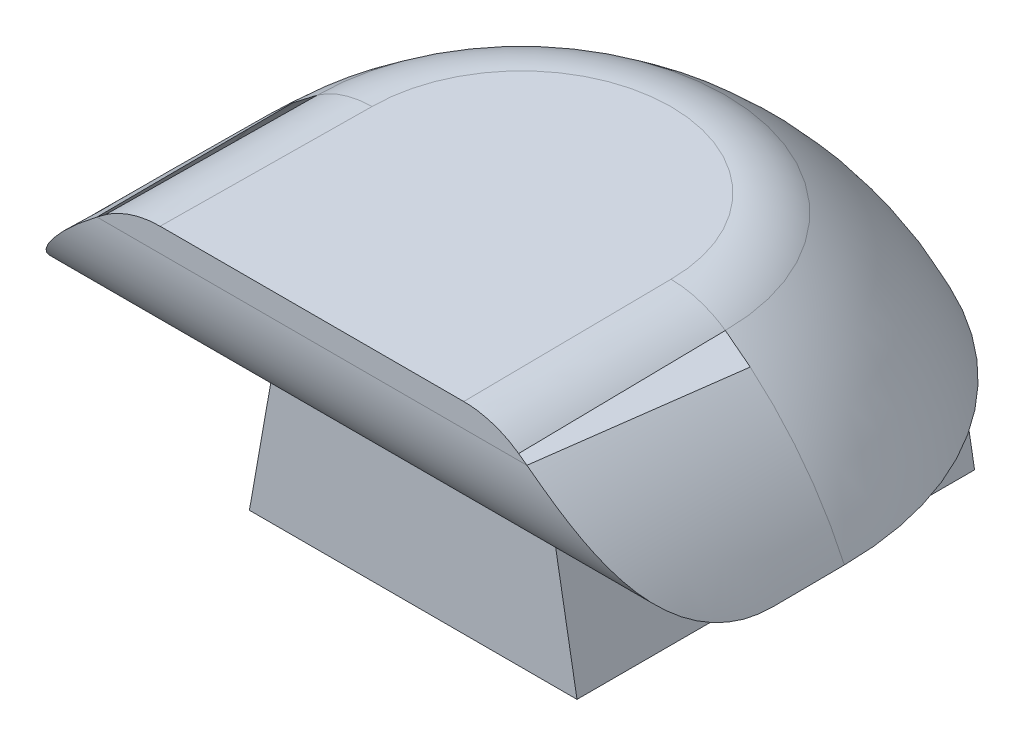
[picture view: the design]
ISO-10303-21;
HEADER;
FILE_DESCRIPTION(('STEP AP214'),'2;1');
FILE_NAME('part.step','',(''),(''),'','','');
FILE_SCHEMA(('AUTOMOTIVE_DESIGN { 1 0 10303 214 1 1 1 1 }'));
ENDSEC;
DATA;
#1=APPLICATION_CONTEXT('core data for automotive mechanical design processes');
#2=APPLICATION_PROTOCOL_DEFINITION('international standard','automotive_design',2000,#1);
#3=PRODUCT_CONTEXT('',#1,'mechanical');
#4=PRODUCT('Part','Part','',(#3));
#5=PRODUCT_RELATED_PRODUCT_CATEGORY('part','',(#4));
#6=PRODUCT_DEFINITION_FORMATION('','',#4);
#7=PRODUCT_DEFINITION_CONTEXT('part definition',#1,'design');
#8=PRODUCT_DEFINITION('design','',#6,#7);
#9=PRODUCT_DEFINITION_SHAPE('','',#8);
#10=(LENGTH_UNIT() NAMED_UNIT(*) SI_UNIT(.MILLI.,.METRE.));
#11=(NAMED_UNIT(*) PLANE_ANGLE_UNIT() SI_UNIT($,.RADIAN.));
#12=(NAMED_UNIT(*) SI_UNIT($,.STERADIAN.) SOLID_ANGLE_UNIT());
#13=UNCERTAINTY_MEASURE_WITH_UNIT(LENGTH_MEASURE(1.E-05),#10,'distance_accuracy_value','');
#14=(GEOMETRIC_REPRESENTATION_CONTEXT(3) GLOBAL_UNCERTAINTY_ASSIGNED_CONTEXT((#13)) GLOBAL_UNIT_ASSIGNED_CONTEXT((#10,
#11,#12)) REPRESENTATION_CONTEXT('',''));
#15=CARTESIAN_POINT('',(0.,0.,0.));
#16=DIRECTION('',(0.,0.,1.));
#17=DIRECTION('',(1.,0.,0.));
#18=AXIS2_PLACEMENT_3D('',#15,#16,#17);
#19=CARTESIAN_POINT('',(-82.1732035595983,3.1,-114.872611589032));
#20=DIRECTION('',(0.,1.,0.));
#21=DIRECTION('',(0.,0.,1.));
#22=AXIS2_PLACEMENT_3D('',#19,#20,#21);
#23=PLANE('',#22);
#24=DIRECTION('',(0.,0.,1.));
#25=VECTOR('',#24,1.);
#26=CARTESIAN_POINT('',(2.93503923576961,3.1,-114.872611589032));
#27=LINE('',#26,#25);
#28=CARTESIAN_POINT('',(2.93503923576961,3.09999999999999,-62.4463343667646));
#29=VERTEX_POINT('',#28);
#30=CARTESIAN_POINT('',(2.93503923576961,3.09999999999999,-54.7963261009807));
#31=VERTEX_POINT('',#30);
#32=EDGE_CURVE('E11',#29,#31,#27,.T.);
#33=ORIENTED_EDGE('',*,*,#32,.F.);
#34=DIRECTION('',(-1.,0.,0.));
#35=VECTOR('',#34,1.);
#36=CARTESIAN_POINT('',(2.93503923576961,3.09999999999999,-62.4463343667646));
#37=LINE('',#36,#35);
#38=CARTESIAN_POINT('',(-2.93503923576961,3.09999999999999,-62.4463343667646));
#39=VERTEX_POINT('',#38);
#40=EDGE_CURVE('E54',#29,#39,#37,.T.);
#41=ORIENTED_EDGE('',*,*,#40,.T.);
#42=DIRECTION('',(0.,0.,-1.));
#43=VECTOR('',#42,1.);
#44=CARTESIAN_POINT('',(-2.93503923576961,3.1,-114.872611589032));
#45=LINE('',#44,#43);
#46=CARTESIAN_POINT('',(-2.93503923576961,3.09999999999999,-54.7963261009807));
#47=VERTEX_POINT('',#46);
#48=EDGE_CURVE('E47',#47,#39,#45,.T.);
#49=ORIENTED_EDGE('',*,*,#48,.F.);
#50=DIRECTION('',(1.,0.,0.));
#51=VECTOR('',#50,1.);
#52=CARTESIAN_POINT('',(-82.1732035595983,3.09999999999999,-54.7963261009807));
#53=LINE('',#52,#51);
#54=CARTESIAN_POINT('',(-6.84025696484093,3.09999999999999,-54.7963261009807));
#55=VERTEX_POINT('',#54);
#56=EDGE_CURVE('E166',#55,#47,#53,.T.);
#57=ORIENTED_EDGE('',*,*,#56,.F.);
#58=CARTESIAN_POINT('',(-6.84025696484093,3.09999999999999,-54.7963261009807));
#59=CARTESIAN_POINT('',(-6.83662078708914,3.09999999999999,-55.3065908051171));
#60=CARTESIAN_POINT('',(-6.83298460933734,3.09999999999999,-55.8168555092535));
#61=CARTESIAN_POINT('',(-6.82934843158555,3.09999999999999,-56.3271202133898));
#62=B_SPLINE_CURVE_WITH_KNOTS('',3,(#58,#59,#60,#61),.UNSPECIFIED.,.F.,.F.,(4,4),(0.,
1.53083297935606),.UNSPECIFIED.);
#63=CARTESIAN_POINT('',(-6.82934843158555,3.09999999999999,-56.3271202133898));
#64=VERTEX_POINT('',#63);
#65=EDGE_CURVE('E435',#55,#64,#62,.T.);
#66=ORIENTED_EDGE('',*,*,#65,.T.);
#67=CARTESIAN_POINT('',(0.,3.09999999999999,-56.3271202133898));
#68=DIRECTION('',(0.,1.,0.));
#69=DIRECTION('',(0.,0.,1.));
#70=AXIS2_PLACEMENT_3D('',#67,#68,#69);
#71=CIRCLE('',#70,6.82934827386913);
#72=CARTESIAN_POINT('',(6.82934827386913,3.09999999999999,-56.3271202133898));
#73=VERTEX_POINT('',#72);
#74=EDGE_CURVE('E289',#73,#64,#71,.T.);
#75=ORIENTED_EDGE('',*,*,#74,.F.);
#76=CARTESIAN_POINT('',(6.82934843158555,3.09999999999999,-56.3271202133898));
#77=CARTESIAN_POINT('',(6.83298460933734,3.09999999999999,-55.8168555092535));
#78=CARTESIAN_POINT('',(6.83662078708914,3.09999999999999,-55.3065908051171));
#79=CARTESIAN_POINT('',(6.84025696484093,3.09999999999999,-54.7963261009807));
#80=B_SPLINE_CURVE_WITH_KNOTS('',3,(#76,#77,#78,#79),.UNSPECIFIED.,.F.,.F.,(4,4),(0.,
1.53083297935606),.UNSPECIFIED.);
#81=CARTESIAN_POINT('',(6.84025696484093,3.09999999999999,-54.7963261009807));
#82=VERTEX_POINT('',#81);
#83=EDGE_CURVE('E234',#73,#82,#80,.T.);
#84=ORIENTED_EDGE('',*,*,#83,.T.);
#85=EDGE_CURVE('E60',#31,#82,#53,.T.);
#86=ORIENTED_EDGE('',*,*,#85,.F.);
#87=EDGE_LOOP('',(#33,#41,#49,#57,#66,#75,#84,#86));
#88=FACE_BOUND('',#87,.T.);
#89=ADVANCED_FACE('F39',(#88),#23,.F.);
#90=CARTESIAN_POINT('',(-4.,-1.95755957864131,-49.8271202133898));
#91=DIRECTION('',(-1.,0.,0.));
#92=DIRECTION('',(0.,0.,1.));
#93=AXIS2_PLACEMENT_3D('',#90,#91,#92);
#94=CYLINDRICAL_SURFACE('',#93,6.5);
#95=CARTESIAN_POINT('',(-3.45109586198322,-1.95755957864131,-49.8271202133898));
#96=DIRECTION('',(-0.999969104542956,0.,-0.00786065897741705));
#97=DIRECTION('',(-0.00786065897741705,0.,0.999969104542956));
#98=AXIS2_PLACEMENT_3D('',#95,#96,#97);
#99=ELLIPSE('',#98,6.50020082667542,6.5);
#100=CARTESIAN_POINT('',(-3.42224907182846,3.40747903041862,-53.4967742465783));
#101=VERTEX_POINT('',#100);
#102=CARTESIAN_POINT('',(-3.42586161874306,3.69445677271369,-53.0372154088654));
#103=VERTEX_POINT('',#102);
#104=EDGE_CURVE('E484',#101,#103,#99,.F.);
#105=ORIENTED_EDGE('',*,*,#104,.F.);
#106=DIRECTION('',(1.,0.,0.));
#107=VECTOR('',#106,1.);
#108=CARTESIAN_POINT('',(-35.9587475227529,3.40747903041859,-53.4967742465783));
#109=LINE('',#108,#107);
#110=CARTESIAN_POINT('',(3.42224907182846,3.40747903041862,-53.4967742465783));
#111=VERTEX_POINT('',#110);
#112=EDGE_CURVE('E427',#101,#111,#109,.T.);
#113=ORIENTED_EDGE('',*,*,#112,.T.);
#114=CARTESIAN_POINT('',(3.45109586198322,-1.95755957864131,-49.8271202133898));
#115=DIRECTION('',(0.999969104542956,0.,-0.00786065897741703));
#116=DIRECTION('',(-0.00786065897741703,0.,-0.999969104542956));
#117=AXIS2_PLACEMENT_3D('',#114,#115,#116);
#118=ELLIPSE('',#117,6.50020082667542,6.5);
#119=CARTESIAN_POINT('',(3.42586161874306,3.69445677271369,-53.0372154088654));
#120=VERTEX_POINT('',#119);
#121=EDGE_CURVE('E482',#120,#111,#118,.F.);
#122=ORIENTED_EDGE('',*,*,#121,.F.);
#123=DIRECTION('',(1.,0.,0.));
#124=VECTOR('',#123,1.);
#125=CARTESIAN_POINT('',(-35.9587475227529,3.69445677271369,-53.0372154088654));
#126=LINE('',#125,#124);
#127=EDGE_CURVE('E489',#120,#103,#126,.F.);
#128=ORIENTED_EDGE('',*,*,#127,.T.);
#129=EDGE_LOOP('',(#105,#113,#122,#128));
#130=FACE_BOUND('',#129,.T.);
#131=ADVANCED_FACE('F41',(#130),#94,.F.);
#132=CARTESIAN_POINT('',(4.,4.99999999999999,20.));
#133=DIRECTION('',(0.999969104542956,0.,-0.00786065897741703));
#134=DIRECTION('',(0.,-1.,0.));
#135=AXIS2_PLACEMENT_3D('',#132,#133,#134);
#136=PLANE('',#135);
#137=ORIENTED_EDGE('',*,*,#121,.T.);
#138=CARTESIAN_POINT('',(3.41203342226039,5.99999999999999,-54.7963261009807));
#139=DIRECTION('',(0.999969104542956,0.,-0.00786065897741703));
#140=DIRECTION('',(0.00786065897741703,0.,0.999969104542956));
#141=AXIS2_PLACEMENT_3D('',#138,#139,#140);
#142=ELLIPSE('',#141,2.90008959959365,2.9);
#143=EDGE_CURVE('E173',#111,#120,#142,.F.);
#144=ORIENTED_EDGE('',*,*,#143,.T.);
#145=EDGE_LOOP('',(#137,#144));
#146=FACE_BOUND('',#145,.T.);
#147=ADVANCED_FACE('F498',(#146),#136,.F.);
#148=CARTESIAN_POINT('',(-4.,-5.2,20.));
#149=DIRECTION('',(-0.999969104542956,0.,-0.00786065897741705));
#150=DIRECTION('',(0.,1.,0.));
#151=AXIS2_PLACEMENT_3D('',#148,#149,#150);
#152=PLANE('',#151);
#153=ORIENTED_EDGE('',*,*,#104,.T.);
#154=CARTESIAN_POINT('',(-3.41203342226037,5.99999999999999,-54.7963261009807));
#155=DIRECTION('',(-0.999969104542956,0.,-0.00786065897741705));
#156=DIRECTION('',(0.00786065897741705,0.,-0.999969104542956));
#157=AXIS2_PLACEMENT_3D('',#154,#155,#156);
#158=ELLIPSE('',#157,2.90008959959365,2.9);
#159=EDGE_CURVE('E178',#103,#101,#158,.F.);
#160=ORIENTED_EDGE('',*,*,#159,.T.);
#161=EDGE_LOOP('',(#153,#160));
#162=FACE_BOUND('',#161,.T.);
#163=ADVANCED_FACE('F208',(#162),#152,.F.);
#164=CARTESIAN_POINT('',(-82.1732035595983,5.99999999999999,-54.7963261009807));
#165=DIRECTION('',(1.,0.,0.));
#166=DIRECTION('',(0.,0.,-1.));
#167=AXIS2_PLACEMENT_3D('',#164,#165,#166);
#168=CYLINDRICAL_SURFACE('',#167,2.9);
#169=CARTESIAN_POINT('',(6.84025696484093,3.09999999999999,-54.7963261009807));
#170=CARTESIAN_POINT('',(6.84078361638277,3.09998963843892,-54.7218055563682));
#171=CARTESIAN_POINT('',(6.84001708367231,3.10287226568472,-54.6472789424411));
#172=CARTESIAN_POINT('',(6.83586250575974,3.11434962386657,-54.4987444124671));
#173=CARTESIAN_POINT('',(6.83247460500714,3.12294404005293,-54.4247364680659));
#174=CARTESIAN_POINT('',(6.82304812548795,3.14575680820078,-54.2778539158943));
#175=CARTESIAN_POINT('',(6.81701287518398,3.15996809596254,-54.2049780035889));
#176=CARTESIAN_POINT('',(6.80223687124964,3.19384526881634,-54.0608070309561));
#177=CARTESIAN_POINT('',(6.79349615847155,3.21351107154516,-53.9895119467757));
#178=CARTESIAN_POINT('',(6.76308846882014,3.28042692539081,-53.7786811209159));
#179=CARTESIAN_POINT('',(6.73723259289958,3.33560405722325,-53.6421451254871));
#180=CARTESIAN_POINT('',(6.6737489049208,3.46449877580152,-53.381252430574));
#181=CARTESIAN_POINT('',(6.63612419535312,3.53821147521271,-53.2568925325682));
#182=CARTESIAN_POINT('',(6.54833093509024,3.70121016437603,-53.0226200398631));
#183=CARTESIAN_POINT('',(6.49809096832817,3.79058391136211,-52.912795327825));
#184=CARTESIAN_POINT('',(6.38509408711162,3.98038208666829,-52.7105658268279));
#185=CARTESIAN_POINT('',(6.32233471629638,4.08080868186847,-52.6181644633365));
#186=CARTESIAN_POINT('',(6.18125604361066,4.29354675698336,-52.4473751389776));
#187=CARTESIAN_POINT('',(6.10230579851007,4.40620326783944,-52.3699437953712));
#188=CARTESIAN_POINT('',(5.93216605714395,4.63406248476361,-52.2347255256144));
#189=CARTESIAN_POINT('',(5.84096798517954,4.7492669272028,-52.1769524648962));
#190=CARTESIAN_POINT('',(5.67470987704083,4.94640624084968,-52.0929883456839));
#191=CARTESIAN_POINT('',(5.60218818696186,5.02870744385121,-52.0624820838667));
#192=CARTESIAN_POINT('',(5.45210084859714,5.1914765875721,-52.0100020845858));
#193=CARTESIAN_POINT('',(5.37453284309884,5.27194364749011,-51.988032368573));
#194=CARTESIAN_POINT('',(5.21491689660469,5.43014955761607,-51.9517057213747));
#195=CARTESIAN_POINT('',(5.13286660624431,5.50788694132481,-51.9373528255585));
#196=CARTESIAN_POINT('',(4.96481972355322,5.65996226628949,-51.9153059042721));
#197=CARTESIAN_POINT('',(4.87882294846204,5.73430004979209,-51.9076121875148));
#198=CARTESIAN_POINT('',(4.75100173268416,5.83978450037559,-51.9005652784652));
#199=CARTESIAN_POINT('',(4.71054389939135,5.8724684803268,-51.898951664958));
#200=CARTESIAN_POINT('',(4.62905087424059,5.93690960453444,-51.8968338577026));
#201=CARTESIAN_POINT('',(4.58801760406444,5.96866907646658,-51.8963265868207));
#202=CARTESIAN_POINT('',(4.54665605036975,5.99999999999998,-51.8963261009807));
#203=B_SPLINE_CURVE_WITH_KNOTS('',3,(#169,#170,#171,#172,#173,#174,#175,#176,#177,#178,#179,
#180,#181,#182,#183,#184,#185,#186,#187,#188,#189,#190,#191,#192,#193,#194,#195,#196,#197,#198,
#199,#200,#201,#202),.UNSPECIFIED.,.F.,.F.,(4,2,2,2,2,2,2,2,2,2,2,2,2,2,2,2,4),(0.,
0.223494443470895,0.44697657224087,0.670178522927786,0.893377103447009,1.33960999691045,
1.78572535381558,2.23442550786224,2.68321378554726,3.1549208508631,3.62695993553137,
3.9680926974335,4.30938596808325,4.65085987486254,4.99234961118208,5.14843733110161,
5.30409035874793),.UNSPECIFIED.);
#204=CARTESIAN_POINT('',(4.54665605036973,5.99999999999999,-51.8963261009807));
#205=VERTEX_POINT('',#204);
#206=EDGE_CURVE('E189',#82,#205,#203,.T.);
#207=ORIENTED_EDGE('',*,*,#206,.T.);
#208=DIRECTION('',(1.,0.,0.));
#209=VECTOR('',#208,1.);
#210=CARTESIAN_POINT('',(-82.1732035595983,5.99999999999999,-51.8963261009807));
#211=LINE('',#210,#209);
#212=CARTESIAN_POINT('',(-4.54665605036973,5.99999999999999,-51.8963261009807));
#213=VERTEX_POINT('',#212);
#214=EDGE_CURVE('E171',#213,#205,#211,.T.);
#215=ORIENTED_EDGE('',*,*,#214,.F.);
#216=CARTESIAN_POINT('',(-4.54665605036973,5.99999999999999,-51.8963261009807));
#217=CARTESIAN_POINT('',(-4.64398797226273,5.92629626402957,-51.8963354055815));
#218=CARTESIAN_POINT('',(-4.73954769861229,5.85013936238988,-51.8991382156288));
#219=CARTESIAN_POINT('',(-4.92677071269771,5.69331054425,-51.9115106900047));
#220=CARTESIAN_POINT('',(-5.01842509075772,5.61262918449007,-51.9210950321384));
#221=CARTESIAN_POINT('',(-5.19781389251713,5.44676866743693,-51.9483353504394));
#222=CARTESIAN_POINT('',(-5.28550857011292,5.36155721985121,-51.966058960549));
#223=CARTESIAN_POINT('',(-5.45539395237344,5.18824518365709,-52.0108184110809));
#224=CARTESIAN_POINT('',(-5.53758973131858,5.10014737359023,-52.0378455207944));
#225=CARTESIAN_POINT('',(-5.67410990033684,4.94665655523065,-52.0935158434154));
#226=CARTESIAN_POINT('',(-5.72989704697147,4.88166103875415,-52.1196842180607));
#227=CARTESIAN_POINT('',(-5.83793596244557,4.75138464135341,-52.1779205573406));
#228=CARTESIAN_POINT('',(-5.89018863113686,4.68610383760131,-52.2099870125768));
#229=CARTESIAN_POINT('',(-5.99074707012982,4.55614280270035,-52.2802347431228));
#230=CARTESIAN_POINT('',(-6.03906400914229,4.49146136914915,-52.3183977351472));
#231=CARTESIAN_POINT('',(-6.1316563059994,4.36333453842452,-52.40109417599));
#232=CARTESIAN_POINT('',(-6.17593360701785,4.29988855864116,-52.4456245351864));
#233=CARTESIAN_POINT('',(-6.2606553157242,4.17451180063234,-52.5415800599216));
#234=CARTESIAN_POINT('',(-6.30106130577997,4.11259999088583,-52.5930641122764));
#235=CARTESIAN_POINT('',(-6.37743665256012,3.99184727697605,-52.7025345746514));
#236=CARTESIAN_POINT('',(-6.41340586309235,3.93300647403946,-52.7605211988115));
#237=CARTESIAN_POINT('',(-6.48084681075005,3.8193371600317,-52.8827746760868));
#238=CARTESIAN_POINT('',(-6.51231652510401,3.76451045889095,-52.9470443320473));
#239=CARTESIAN_POINT('',(-6.57073476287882,3.65983699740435,-53.0814244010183));
#240=CARTESIAN_POINT('',(-6.5976839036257,3.60998955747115,-53.1515340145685));
#241=CARTESIAN_POINT('',(-6.64418850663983,3.52170982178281,-53.2883806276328));
#242=CARTESIAN_POINT('',(-6.66424197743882,3.48262491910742,-53.3545290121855));
#243=CARTESIAN_POINT('',(-6.70097420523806,3.40949100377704,-53.4904841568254));
#244=CARTESIAN_POINT('',(-6.71765172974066,3.37544383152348,-53.560292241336));
#245=CARTESIAN_POINT('',(-6.74770122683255,3.31288270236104,-53.7029555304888));
#246=CARTESIAN_POINT('',(-6.7610762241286,3.28436368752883,-53.7758078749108));
#247=CARTESIAN_POINT('',(-6.78464044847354,3.23318163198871,-53.9240446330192));
#248=CARTESIAN_POINT('',(-6.79482879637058,3.21052020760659,-53.9994297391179));
#249=CARTESIAN_POINT('',(-6.81671945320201,3.16090793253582,-54.1928941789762));
#250=CARTESIAN_POINT('',(-6.82633682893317,3.13810331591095,-54.3123236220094));
#251=CARTESIAN_POINT('',(-6.83548569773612,3.11526377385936,-54.4930139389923));
#252=CARTESIAN_POINT('',(-6.83765580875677,3.1095451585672,-54.5534990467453));
#253=CARTESIAN_POINT('',(-6.84025670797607,3.10191300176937,-54.674758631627));
#254=CARTESIAN_POINT('',(-6.8406871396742,3.10000024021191,-54.7355331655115));
#255=CARTESIAN_POINT('',(-6.84025696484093,3.09999999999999,-54.7963261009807));
#256=B_SPLINE_CURVE_WITH_KNOTS('',3,(#216,#217,#218,#219,#220,#221,#222,#223,#224,#225,#226,
#227,#228,#229,#230,#231,#232,#233,#234,#235,#236,#237,#238,#239,#240,#241,#242,#243,#244,#245,
#246,#247,#248,#249,#250,#251,#252,#253,#254,#255),.UNSPECIFIED.,.F.,.F.,(4,2,2,2,2,2,2,2,2,2,2,
2,2,2,2,2,2,2,2,4),(0.,0.366302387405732,0.733400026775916,1.10360488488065,1.47346327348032,
1.74191431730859,2.0102967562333,2.27788893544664,2.54535170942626,2.81524099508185,
3.08513917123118,3.35515830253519,3.62514053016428,3.86305306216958,4.10105229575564,
4.3388327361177,4.57667871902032,4.94123238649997,5.12349321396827,5.30579138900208),.UNSPECIFIED.);
#257=EDGE_CURVE('E181',#213,#55,#256,.T.);
#258=ORIENTED_EDGE('',*,*,#257,.T.);
#259=ORIENTED_EDGE('',*,*,#56,.T.);
#260=EDGE_CURVE('E164',#47,#31,#53,.T.);
#261=ORIENTED_EDGE('',*,*,#260,.T.);
#262=ORIENTED_EDGE('',*,*,#85,.T.);
#263=EDGE_LOOP('',(#207,#215,#258,#259,#261,#262));
#264=FACE_BOUND('',#263,.T.);
#265=ORIENTED_EDGE('',*,*,#159,.F.);
#266=ORIENTED_EDGE('',*,*,#127,.F.);
#267=ORIENTED_EDGE('',*,*,#143,.F.);
#268=ORIENTED_EDGE('',*,*,#112,.F.);
#269=EDGE_LOOP('',(#265,#266,#267,#268));
#270=FACE_BOUND('',#269,.T.);
#271=ADVANCED_FACE('F202',(#264,#270),#168,.T.);
#272=CARTESIAN_POINT('',(-82.1732035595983,5.99999999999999,-51.8963261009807));
#273=DIRECTION('',(0.,0.,-1.));
#274=DIRECTION('',(-1.,0.,0.));
#275=AXIS2_PLACEMENT_3D('',#272,#273,#274);
#276=PLANE('',#275);
#277=CARTESIAN_POINT('',(4.54665605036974,5.99999999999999,-51.8963261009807));
#278=CARTESIAN_POINT('',(4.4987948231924,6.03625413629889,-51.8963261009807));
#279=CARTESIAN_POINT('',(4.45051392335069,6.0719258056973,-51.8963261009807));
#280=CARTESIAN_POINT('',(4.35311277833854,6.14210421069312,-51.8963261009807));
#281=CARTESIAN_POINT('',(4.3039925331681,6.17661094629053,-51.8963261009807));
#282=CARTESIAN_POINT('',(4.25445261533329,6.21053521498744,-51.8963261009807));
#283=B_SPLINE_CURVE_WITH_KNOTS('',3,(#277,#278,#279,#280,#281,#282),.UNSPECIFIED.,.F.,.F.,(4,2,
4),(0.,0.180087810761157,0.360175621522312),.UNSPECIFIED.);
#284=CARTESIAN_POINT('',(4.37212359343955,6.12829752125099,-51.8963261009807));
#285=VERTEX_POINT('',#284);
#286=EDGE_CURVE('E282',#205,#285,#283,.T.);
#287=ORIENTED_EDGE('',*,*,#286,.T.);
#288=CARTESIAN_POINT('',(3.05932211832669,6.5,-65.6550908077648));
#289=CARTESIAN_POINT('',(3.67544909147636,6.49999999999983,-65.6619186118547));
#290=CARTESIAN_POINT('',(4.18475579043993,6.15325240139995,-65.6675626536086));
#291=CARTESIAN_POINT('',(3.07657375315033,6.5,-64.0983259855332));
#292=CARTESIAN_POINT('',(3.69545583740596,6.49999999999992,-64.1045709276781));
#293=CARTESIAN_POINT('',(4.2061557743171,6.15042773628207,-64.1108242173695));
#294=CARTESIAN_POINT('',(3.09378497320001,6.5,-62.5415607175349));
#295=CARTESIAN_POINT('',(3.71540190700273,6.49999999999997,-62.5478249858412));
#296=CARTESIAN_POINT('',(4.22748112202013,6.14760430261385,-62.5540847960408));
#297=CARTESIAN_POINT('',(3.12812658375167,6.5,-59.4280292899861));
#298=CARTESIAN_POINT('',(3.75518796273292,6.50000000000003,-59.4343320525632));
#299=CARTESIAN_POINT('',(4.26998254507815,6.14195989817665,-59.4406039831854));
#300=CARTESIAN_POINT('',(3.14525697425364,6.5,-57.8712631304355));
#301=CARTESIAN_POINT('',(3.77502787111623,6.50000000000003,-57.8775847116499));
#302=CARTESIAN_POINT('',(4.29115862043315,6.13913892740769,-57.8838625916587));
#303=CARTESIAN_POINT('',(3.16234694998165,6.5,-56.3144965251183));
#304=CARTESIAN_POINT('',(3.79480689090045,6.5,-56.321439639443));
#305=CARTESIAN_POINT('',(4.31226005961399,6.13631918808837,-56.3271202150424));
#306=CARTESIAN_POINT('',(3.16796316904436,6.5,-55.8029054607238));
#307=CARTESIAN_POINT('',(3.8013102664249,6.5,-55.8097894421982));
#308=CARTESIAN_POINT('',(4.31919474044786,6.13539257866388,-55.8155371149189));
#309=CARTESIAN_POINT('',(3.17357504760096,6.5,-55.291314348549));
#310=CARTESIAN_POINT('',(3.80780715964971,6.5,-55.2982044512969));
#311=CARTESIAN_POINT('',(4.3261215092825,6.13446610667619,-55.3039539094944));
#312=CARTESIAN_POINT('',(3.25978746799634,6.5,-47.4259239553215));
#313=CARTESIAN_POINT('',(3.90777657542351,6.5,-47.4194753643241));
#314=CARTESIAN_POINT('',(4.4324950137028,6.12022439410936,-47.4386841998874));
#315=CARTESIAN_POINT('',(3.33949645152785,6.5,-40.0721148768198));
#316=CARTESIAN_POINT('',(3.99991556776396,6.49999999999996,-40.0657247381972));
#317=CARTESIAN_POINT('',(4.53032099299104,6.10693868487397,-40.0849761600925));
#318=CARTESIAN_POINT('',(3.49714999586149,6.5,-25.3644773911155));
#319=CARTESIAN_POINT('',(4.18195670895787,6.49999999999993,-25.3581954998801));
#320=CARTESIAN_POINT('',(4.72289271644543,6.08046334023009,-25.3775197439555));
#321=CARTESIAN_POINT('',(3.57509455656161,6.5,-18.0106489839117));
#322=CARTESIAN_POINT('',(4.27185000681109,6.49999999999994,-18.0044637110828));
#323=CARTESIAN_POINT('',(4.81763846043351,6.06727370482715,-18.0237713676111));
#324=CARTESIAN_POINT('',(3.6906048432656,6.49999999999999,-6.99024791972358));
#325=CARTESIAN_POINT('',(4.40481060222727,6.49999999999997,-6.99432855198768));
#326=CARTESIAN_POINT('',(4.9574162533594,6.04761808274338,-7.00347678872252));
#327=CARTESIAN_POINT('',(3.72882079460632,6.49999999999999,-3.32368206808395));
#328=CARTESIAN_POINT('',(4.44881624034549,6.49999999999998,-3.32780698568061));
#329=CARTESIAN_POINT('',(5.00355511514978,6.04109681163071,-3.33694413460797));
#330=CARTESIAN_POINT('',(3.83478660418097,6.49999999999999,6.899731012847));
#331=CARTESIAN_POINT('',(4.57086101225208,6.50000000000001,6.90295605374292));
#332=CARTESIAN_POINT('',(5.13120476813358,6.0229740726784,6.88638207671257));
#333=CARTESIAN_POINT('',(3.90207066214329,6.49999999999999,13.4565830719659));
#334=CARTESIAN_POINT('',(4.64821969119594,6.50000000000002,13.4597160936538));
#335=CARTESIAN_POINT('',(5.2119285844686,6.01142020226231,13.44318495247));
#336=CARTESIAN_POINT('',(3.96869525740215,6.49999999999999,20.0134418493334));
#337=CARTESIAN_POINT('',(4.72462420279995,6.49999999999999,20.0057606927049));
#338=CARTESIAN_POINT('',(5.29155383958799,5.99995483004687,19.9999999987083));
#339=CARTESIAN_POINT('',(3.97658337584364,6.49999999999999,20.7897345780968));
#340=CARTESIAN_POINT('',(4.73368678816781,6.49999999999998,20.7822003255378));
#341=CARTESIAN_POINT('',(5.30098107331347,5.99859734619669,20.7762875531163));
#342=CARTESIAN_POINT('',(3.98446224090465,6.49999999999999,21.5660274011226));
#343=CARTESIAN_POINT('',(4.74273590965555,6.49999999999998,21.5584869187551));
#344=CARTESIAN_POINT('',(5.31039288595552,5.99724113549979,21.5525752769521));
#345=CARTESIAN_POINT('',(4.14481111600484,6.49999999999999,37.3834412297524));
#346=CARTESIAN_POINT('',(4.92753807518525,6.49999999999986,37.4322759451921));
#347=CARTESIAN_POINT('',(5.50185157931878,5.96963397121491,37.3698867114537));
#348=CARTESIAN_POINT('',(4.29383527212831,6.49999999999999,52.4245972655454));
#349=CARTESIAN_POINT('',(5.09822644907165,6.49999999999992,52.4713070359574));
#350=CARTESIAN_POINT('',(5.67815807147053,5.94386826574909,52.4109731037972));
#351=CARTESIAN_POINT('',(4.58570126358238,6.49999999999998,82.506970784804));
#352=CARTESIAN_POINT('',(5.4317793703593,6.50000000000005,82.5547478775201));
#353=CARTESIAN_POINT('',(6.02055984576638,5.89364265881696,82.4932436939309));
#354=CARTESIAN_POINT('',(4.72854309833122,6.49999999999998,97.5481882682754));
#355=CARTESIAN_POINT('',(5.59453539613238,6.50000000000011,97.5946309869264));
#356=CARTESIAN_POINT('',(6.18665512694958,5.86918275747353,97.5344278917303));
#357=CARTESIAN_POINT('',(4.86865765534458,6.49999999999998,112.589430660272));
#358=CARTESIAN_POINT('',(5.75320024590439,6.49999999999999,112.581189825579));
#359=CARTESIAN_POINT('',(6.34829490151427,5.84554211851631,112.575645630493));
#360=(BOUNDED_SURFACE() B_SPLINE_SURFACE(3,2,((#288,#289,#290),(#291,#292,#293),(#294,#295,
#296),(#297,#298,#299),(#300,#301,#302),(#303,#304,#305),(#306,#307,#308),(#309,#310,#311),
(#312,#313,#314),(#315,#316,#317),(#318,#319,#320),(#321,#322,#323),(#324,#325,#326),(#327,#328,
#329),(#330,#331,#332),(#333,#334,#335),(#336,#337,#338),(#339,#340,#341),(#342,#343,#344),
(#345,#346,#347),(#348,#349,#350),(#351,#352,#353),(#354,#355,#356),(#357,#358,#359)),
.UNSPECIFIED.,.F.,.F.,.F.) B_SPLINE_SURFACE_WITH_KNOTS((4,2,3,2,2,2,2,3,2,2,4),(3,3),(0.,
4.67058121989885,9.34116243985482,10.8760281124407,32.9387510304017,55.0014752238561,
66.0017702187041,85.6733619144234,88.0023603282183,133.128041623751,178.253727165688),(0.,1.),
.UNSPECIFIED.) GEOMETRIC_REPRESENTATION_ITEM() RATIONAL_B_SPLINE_SURFACE(((1.,0.955674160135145,
1.),(1.,0.955304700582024,1.),(1.,0.954935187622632,1.),(1.,0.9541960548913,1.),(1.,
0.95382643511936,1.),(1.,0.953456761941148,1.),(1.,0.953335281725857,1.),(1.,0.953213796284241,
1.),(1.,0.951345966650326,1.),(1.,0.949598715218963,1.),(1.,0.946107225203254,1.),(1.,
0.944362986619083,1.),(1.,0.941756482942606,1.),(1.,0.940890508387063,1.),(1.,0.938480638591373,
1.),(1.,0.936940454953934,1.),(1.,0.935408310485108,1.),(1.,0.935226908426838,1.),(1.,
0.935045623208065,1.),(1.,0.931354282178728,1.),(1.,0.927889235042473,1.),(1.,0.921098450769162,
1.),(1.,0.917772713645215,1.),(1.,0.914541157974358,1.))) REPRESENTATION_ITEM('') SURFACE());
#361=CARTESIAN_POINT('',(4.37212359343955,6.12829752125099,-51.8963261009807));
#362=CARTESIAN_POINT('',(4.32573479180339,6.16137963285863,-51.8963261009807));
#363=CARTESIAN_POINT('',(4.27795627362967,6.192462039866,-51.8963261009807));
#364=CARTESIAN_POINT('',(4.17992144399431,6.25044260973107,-51.8963261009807));
#365=CARTESIAN_POINT('',(4.12966501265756,6.27734056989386,-51.8963261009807));
#366=CARTESIAN_POINT('',(3.97833983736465,6.3501756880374,-51.8963261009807));
#367=CARTESIAN_POINT('',(3.87423921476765,6.39000843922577,-51.8963261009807));
#368=CARTESIAN_POINT('',(3.67823129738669,6.44683111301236,-51.8963261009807));
#369=CARTESIAN_POINT('',(3.58707327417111,6.46647276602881,-51.8963261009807));
#370=CARTESIAN_POINT('',(3.40090326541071,6.49321522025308,-51.8963261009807));
#371=CARTESIAN_POINT('',(3.30585058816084,6.50003299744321,-51.8963261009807));
#372=CARTESIAN_POINT('',(3.21074154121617,6.5,-51.8963261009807));
#373=B_SPLINE_CURVE_WITH_KNOTS('',3,(#361,#362,#363,#364,#365,#366,#367,#368,#369,#370,#371,
#372),.UNSPECIFIED.,.F.,.F.,(4,2,2,2,2,4),(0.,0.170819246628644,0.341646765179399,
0.674313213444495,0.953202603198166,1.2381780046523),.UNSPECIFIED.);
#374=CARTESIAN_POINT('',(3.21074154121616,6.5,-51.8963261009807));
#375=VERTEX_POINT('',#374);
#376=EDGE_CURVE('E290',#285,#375,#373,.T.);
#377=ORIENTED_EDGE('',*,*,#376,.T.);
#378=DIRECTION('',(-1.,0.,0.));
#379=VECTOR('',#378,1.);
#380=CARTESIAN_POINT('',(-10.4110305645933,6.5,-51.8963261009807));
#381=LINE('',#380,#379);
#382=CARTESIAN_POINT('',(-3.2107415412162,6.49999999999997,-51.8963261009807));
#383=VERTEX_POINT('',#382);
#384=EDGE_CURVE('E687',#375,#383,#381,.T.);
#385=ORIENTED_EDGE('',*,*,#384,.T.);
#386=CARTESIAN_POINT('',(-3.22422841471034,6.5,-50.6615298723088));
#387=CARTESIAN_POINT('',(-3.86642901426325,6.5,-50.6685398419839));
#388=CARTESIAN_POINT('',(-4.38856583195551,6.12608636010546,-50.6742392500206));
#389=CARTESIAN_POINT('',(-3.21796315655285,6.5,-51.2355054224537));
#390=CARTESIAN_POINT('',(-3.85918110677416,6.5,-51.2424265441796));
#391=CARTESIAN_POINT('',(-4.38085052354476,6.12712471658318,-51.2482063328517));
#392=CARTESIAN_POINT('',(-3.21169245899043,6.5,-51.8094809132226));
#393=CARTESIAN_POINT('',(-3.85192511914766,6.5,-51.8163953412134));
#394=CARTESIAN_POINT('',(-4.37312539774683,6.12816327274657,-51.8221732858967));
#395=CARTESIAN_POINT('',(-3.19914016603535,6.5,-52.9574317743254));
#396=CARTESIAN_POINT('',(-3.83739899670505,6.5,-52.9643327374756));
#397=CARTESIAN_POINT('',(-4.35765540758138,6.13024077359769,-52.9701069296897));
#398=CARTESIAN_POINT('',(-3.19285857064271,6.5,-53.5314071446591));
#399=CARTESIAN_POINT('',(-3.83012886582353,6.5,-53.5383013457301));
#400=CARTESIAN_POINT('',(-4.3499105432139,6.13127971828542,-53.5440736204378));
#401=CARTESIAN_POINT('',(-3.18028446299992,6.5,-54.6793577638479));
#402=CARTESIAN_POINT('',(-3.81557440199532,6.5,-54.6862383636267));
#403=CARTESIAN_POINT('',(-4.33440097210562,6.13335798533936,-54.692006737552));
#404=CARTESIAN_POINT('',(-3.1739919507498,6.5,-55.2533330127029));
#405=CARTESIAN_POINT('',(-3.80829007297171,6.5,-55.2602067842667));
#406=CARTESIAN_POINT('',(-4.3266362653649,6.13439730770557,-55.2659731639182));
#407=CARTESIAN_POINT('',(-3.16591206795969,6.5,-55.9897043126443));
#408=CARTESIAN_POINT('',(-3.79893466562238,6.5,-55.996644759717));
#409=CARTESIAN_POINT('',(-4.31666187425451,6.13573092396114,-56.0023330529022));
#410=CARTESIAN_POINT('',(-3.16412972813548,6.5,-56.1521004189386));
#411=CARTESIAN_POINT('',(-3.79687110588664,6.5,-56.1590389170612));
#412=CARTESIAN_POINT('',(-4.31446136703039,6.13602504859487,-56.1647266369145));
#413=CARTESIAN_POINT('',(-3.16234695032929,6.5,-56.3144965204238));
#414=CARTESIAN_POINT('',(-3.79480689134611,6.5,-56.3214396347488));
#415=CARTESIAN_POINT('',(-4.31226006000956,6.13631918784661,-56.3271202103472));
#416=CARTESIAN_POINT('',(-3.15782584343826,6.5,-56.726075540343));
#417=CARTESIAN_POINT('',(-3.78957078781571,6.5,-56.7330980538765));
#418=CARTESIAN_POINT('',(-4.30667589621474,6.13706474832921,-56.7386927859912));
#419=CARTESIAN_POINT('',(-3.15330473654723,6.5,-57.1376545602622));
#420=CARTESIAN_POINT('',(-3.78433575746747,6.5,-57.1446721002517));
#421=CARTESIAN_POINT('',(-4.30109173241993,6.13781030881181,-57.1502653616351));
#422=CARTESIAN_POINT('',(-3.1487836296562,6.5,-57.5492335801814));
#423=CARTESIAN_POINT('',(-3.77910179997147,6.5,-57.5561617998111));
#424=CARTESIAN_POINT('',(-4.29550756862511,6.13855586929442,-57.5618379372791));
#425=(BOUNDED_SURFACE() B_SPLINE_SURFACE(3,2,((#386,#387,#388),(#389,#390,#391),(#392,#393,
#394),(#395,#396,#397),(#398,#399,#400),(#401,#402,#403),(#404,#405,#406),(#407,#408,#409),
(#410,#411,#412),(#413,#414,#415),(#416,#417,#418),(#419,#420,#421),(#422,#423,#424)),
.UNSPECIFIED.,.F.,.F.,.F.) B_SPLINE_SURFACE_WITH_KNOTS((4,2,2,2,3,4),(3,3),(0.,1.72202923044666,
3.44405845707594,5.16608767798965,5.65330533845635,6.88811689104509),(0.,1.),
.UNSPECIFIED.) GEOMETRIC_REPRESENTATION_ITEM() RATIONAL_B_SPLINE_SURFACE(((1.,0.952114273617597,
1.),(1.,0.952250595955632,1.),(1.,0.952386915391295,1.),(1.,0.952659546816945,1.),(1.,
0.952795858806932,1.),(1.,0.953068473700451,1.),(1.,0.953204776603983,1.),(1.,0.953379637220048,
1.),(1.,0.953418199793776,1.),(1.,0.953456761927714,1.),(1.,0.953554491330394,1.),(1.,
0.953652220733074,1.),(1.,0.953749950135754,1.))) REPRESENTATION_ITEM('') SURFACE());
#426=CARTESIAN_POINT('',(-3.21074154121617,6.5,-51.8963261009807));
#427=CARTESIAN_POINT('',(-3.26771881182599,6.49999940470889,-51.8963261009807));
#428=CARTESIAN_POINT('',(-3.32466645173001,6.49756391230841,-51.8963261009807));
#429=CARTESIAN_POINT('',(-3.43814960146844,6.48784769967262,-51.8963261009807));
#430=CARTESIAN_POINT('',(-3.49468509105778,6.48056674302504,-51.8963261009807));
#431=CARTESIAN_POINT('',(-3.66018106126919,6.45200283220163,-51.8963261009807));
#432=CARTESIAN_POINT('',(-3.76806563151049,6.4239895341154,-51.8963261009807));
#433=CARTESIAN_POINT('',(-3.96064200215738,6.35644505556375,-51.8963261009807));
#434=CARTESIAN_POINT('',(-4.04626355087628,6.3195082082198,-51.8963261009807));
#435=CARTESIAN_POINT('',(-4.2133627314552,6.23318633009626,-51.8963261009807));
#436=CARTESIAN_POINT('',(-4.29470916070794,6.18354724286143,-51.8963261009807));
#437=CARTESIAN_POINT('',(-4.37212359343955,6.12829752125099,-51.8963261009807));
#438=B_SPLINE_CURVE_WITH_KNOTS('',3,(#426,#427,#428,#429,#430,#431,#432,#433,#434,#435,#436,
#437),.UNSPECIFIED.,.F.,.F.,(4,2,2,2,2,4),(0.,0.17082090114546,0.341650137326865,
0.674319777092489,0.953205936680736,1.23817798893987),.UNSPECIFIED.);
#439=CARTESIAN_POINT('',(-4.37212359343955,6.12829752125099,-51.8963261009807));
#440=VERTEX_POINT('',#439);
#441=EDGE_CURVE('E429',#383,#440,#438,.T.);
#442=ORIENTED_EDGE('',*,*,#441,.T.);
#443=CARTESIAN_POINT('',(-4.25445261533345,6.21053521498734,-51.8963261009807));
#444=CARTESIAN_POINT('',(-4.30399253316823,6.17661094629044,-51.8963261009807));
#445=CARTESIAN_POINT('',(-4.35311277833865,6.14210421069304,-51.8963261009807));
#446=CARTESIAN_POINT('',(-4.45051392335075,6.07192580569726,-51.8963261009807));
#447=CARTESIAN_POINT('',(-4.49879482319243,6.03625413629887,-51.8963261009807));
#448=CARTESIAN_POINT('',(-4.54665605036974,5.99999999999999,-51.8963261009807));
#449=B_SPLINE_CURVE_WITH_KNOTS('',3,(#443,#444,#445,#446,#447,#448),.UNSPECIFIED.,.F.,.F.,(4,2,
4),(0.,0.180087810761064,0.360175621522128),.UNSPECIFIED.);
#450=EDGE_CURVE('E466',#440,#213,#449,.T.);
#451=ORIENTED_EDGE('',*,*,#450,.T.);
#452=ORIENTED_EDGE('',*,*,#214,.T.);
#453=EDGE_LOOP('',(#287,#377,#385,#442,#451,#452));
#454=FACE_BOUND('',#453,.T.);
#455=ADVANCED_FACE('F207',(#454),#276,.F.);
#456=CARTESIAN_POINT('',(4.31226006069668,6.13631918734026,-56.3271202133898));
#457=CARTESIAN_POINT('',(4.14386290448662,6.25465923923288,-56.3271202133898));
#458=CARTESIAN_POINT('',(3.9615418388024,6.34485773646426,-56.3271202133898));
#459=CARTESIAN_POINT('',(3.56905924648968,6.46897165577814,-56.3271202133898));
#460=CARTESIAN_POINT('',(3.36802850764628,6.5,-56.3271202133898));
#461=CARTESIAN_POINT('',(3.16220836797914,6.5,-56.3271202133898));
#462=B_SPLINE_CURVE_WITH_KNOTS('',3,(#456,#457,#458,#459,#460,#461),.UNSPECIFIED.,.F.,.F.,(4,2,
4),(0.,0.5,1.),.UNSPECIFIED.);
#463=CARTESIAN_POINT('',(0.,6.5,-56.3271202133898));
#464=DIRECTION('',(0.,1.,0.));
#465=AXIS1_PLACEMENT('',#463,#464);
#466=SURFACE_OF_REVOLUTION('',#462,#465);
#467=CARTESIAN_POINT('',(0.,6.13631906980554,-56.3271202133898));
#468=DIRECTION('',(0.,1.,0.));
#469=DIRECTION('',(-1.,0.,0.));
#470=AXIS2_PLACEMENT_3D('',#467,#468,#469);
#471=CIRCLE('',#470,4.31225997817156);
#472=CARTESIAN_POINT('',(4.31189835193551,6.13657417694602,-56.3271202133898));
#473=VERTEX_POINT('',#472);
#474=CARTESIAN_POINT('',(-4.31189775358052,6.13657332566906,-56.3271202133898));
#475=VERTEX_POINT('',#474);
#476=EDGE_CURVE('E305',#473,#475,#471,.T.);
#477=ORIENTED_EDGE('',*,*,#476,.T.);
#478=CARTESIAN_POINT('',(-4.31226006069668,6.13631918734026,-56.3271202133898));
#479=CARTESIAN_POINT('',(-4.26999782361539,6.16601946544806,-56.3271202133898));
#480=CARTESIAN_POINT('',(-4.22659904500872,6.19407030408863,-56.3271202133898));
#481=CARTESIAN_POINT('',(-4.13776506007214,6.24673136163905,-56.3271202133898));
#482=CARTESIAN_POINT('',(-4.09232996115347,6.27134176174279,-56.3271202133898));
#483=CARTESIAN_POINT('',(-3.95550342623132,6.33872797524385,-56.3271202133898));
#484=CARTESIAN_POINT('',(-3.86157374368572,6.37646858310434,-56.3271202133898));
#485=CARTESIAN_POINT('',(-3.6690833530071,6.4373430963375,-56.3271202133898));
#486=CARTESIAN_POINT('',(-3.57052213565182,6.46047539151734,-56.3271202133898));
#487=CARTESIAN_POINT('',(-3.41981251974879,6.48401668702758,-56.3271202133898));
#488=CARTESIAN_POINT('',(-3.36848266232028,6.49000582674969,-56.3271202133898));
#489=CARTESIAN_POINT('',(-3.2655108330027,6.49799789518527,-56.3271202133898));
#490=CARTESIAN_POINT('',(-3.21386884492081,6.50000061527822,-56.3271202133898));
#491=CARTESIAN_POINT('',(-3.16220836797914,6.5,-56.3271202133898));
#492=B_SPLINE_CURVE_WITH_KNOTS('',3,(#478,#479,#480,#481,#482,#483,#484,#485,#486,#487,#488,
#489,#490,#491),.UNSPECIFIED.,.F.,.F.,(4,2,2,2,2,2,4),(0.,0.154888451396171,0.309768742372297,
0.612225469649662,0.914715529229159,1.06961332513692,1.22451922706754),.UNSPECIFIED.);
#493=CARTESIAN_POINT('',(-3.16220836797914,6.5,-56.3271202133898));
#494=VERTEX_POINT('',#493);
#495=EDGE_CURVE('E323',#475,#494,#492,.T.);
#496=ORIENTED_EDGE('',*,*,#495,.T.);
#497=CARTESIAN_POINT('',(0.,6.5,-56.3271202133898));
#498=DIRECTION('',(0.,1.,0.));
#499=DIRECTION('',(-1.,0.,0.));
#500=AXIS2_PLACEMENT_3D('',#497,#498,#499);
#501=CIRCLE('',#500,3.16220836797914);
#502=CARTESIAN_POINT('',(3.16220836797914,6.5,-56.3271202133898));
#503=VERTEX_POINT('',#502);
#504=EDGE_CURVE('E301',#503,#494,#501,.T.);
#505=ORIENTED_EDGE('',*,*,#504,.F.);
#506=CARTESIAN_POINT('',(3.16220836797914,6.5,-56.3271202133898));
#507=CARTESIAN_POINT('',(3.21386124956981,6.50000061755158,-56.3271202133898));
#508=CARTESIAN_POINT('',(3.26549565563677,6.49799848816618,-56.3271202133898));
#509=CARTESIAN_POINT('',(3.36845244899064,6.49000876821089,-56.3271202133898));
#510=CARTESIAN_POINT('',(3.41977485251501,6.48402138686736,-56.3271202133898));
#511=CARTESIAN_POINT('',(3.57046318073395,6.46048693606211,-56.3271202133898));
#512=CARTESIAN_POINT('',(3.66901090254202,6.43736130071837,-56.3271202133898));
#513=CARTESIAN_POINT('',(3.86150400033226,6.37649534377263,-56.3271202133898));
#514=CARTESIAN_POINT('',(3.95544856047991,6.33875244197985,-56.3271202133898));
#515=CARTESIAN_POINT('',(4.09229644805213,6.27135959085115,-56.3271202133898));
#516=CARTESIAN_POINT('',(4.13773865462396,6.24674634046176,-56.3271202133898));
#517=CARTESIAN_POINT('',(4.22658628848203,6.19407855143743,-56.3271202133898));
#518=CARTESIAN_POINT('',(4.26999160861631,6.16602383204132,-56.3271202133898));
#519=CARTESIAN_POINT('',(4.31226006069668,6.13631918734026,-56.3271202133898));
#520=B_SPLINE_CURVE_WITH_KNOTS('',3,(#506,#507,#508,#509,#510,#511,#512,#513,#514,#515,#516,
#517,#518,#519),.UNSPECIFIED.,.F.,.F.,(4,2,2,2,2,2,4),(0.,0.154883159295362,0.309758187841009,
0.612204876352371,0.914704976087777,1.06960803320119,1.22451922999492),.UNSPECIFIED.);
#521=EDGE_CURVE('E355',#503,#473,#520,.T.);
#522=ORIENTED_EDGE('',*,*,#521,.T.);
#523=EDGE_LOOP('',(#477,#496,#505,#522));
#524=FACE_BOUND('',#523,.T.);
#525=ADVANCED_FACE('F330',(#524),#466,.T.);
#526=ORIENTED_EDGE('',*,*,#441,.F.);
#527=CARTESIAN_POINT('',(-3.1487836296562,6.5,-57.5492335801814));
#528=CARTESIAN_POINT('',(-3.15330473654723,6.5,-57.1376545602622));
#529=CARTESIAN_POINT('',(-3.15782584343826,6.5,-56.726075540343));
#530=CARTESIAN_POINT('',(-3.16234695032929,6.5,-56.3144965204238));
#531=CARTESIAN_POINT('',(-3.16412972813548,6.5,-56.1521004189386));
#532=CARTESIAN_POINT('',(-3.16591206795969,6.5,-55.9897043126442));
#533=CARTESIAN_POINT('',(-3.1739919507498,6.5,-55.2533330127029));
#534=CARTESIAN_POINT('',(-3.18028446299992,6.5,-54.6793577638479));
#535=CARTESIAN_POINT('',(-3.19285857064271,6.5,-53.5314071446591));
#536=CARTESIAN_POINT('',(-3.19914016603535,6.5,-52.9574317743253));
#537=CARTESIAN_POINT('',(-3.21169245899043,6.5,-51.8094809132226));
#538=CARTESIAN_POINT('',(-3.21796315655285,6.5,-51.2355054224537));
#539=CARTESIAN_POINT('',(-3.22422841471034,6.5,-50.6615298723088));
#540=B_SPLINE_CURVE_WITH_KNOTS('',3,(#527,#528,#529,#530,#531,#532,#533,#534,#535,#536,#537,
#538,#539),.UNSPECIFIED.,.F.,.F.,(4,3,2,2,2,4),(0.,1.23481155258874,1.72202921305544,
3.44405843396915,5.16608766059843,6.88811689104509),.UNSPECIFIED.);
#541=EDGE_CURVE('E423',#494,#383,#540,.T.);
#542=ORIENTED_EDGE('',*,*,#541,.F.);
#543=ORIENTED_EDGE('',*,*,#495,.F.);
#544=CARTESIAN_POINT('',(-4.38856583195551,6.12608636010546,-50.6742392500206));
#545=CARTESIAN_POINT('',(-4.38085052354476,6.12712471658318,-51.2482063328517));
#546=CARTESIAN_POINT('',(-4.37312539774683,6.12816327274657,-51.8221732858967));
#547=CARTESIAN_POINT('',(-4.35765540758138,6.13024077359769,-52.9701069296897));
#548=CARTESIAN_POINT('',(-4.3499105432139,6.13127971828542,-53.5440736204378));
#549=CARTESIAN_POINT('',(-4.33440097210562,6.13335798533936,-54.692006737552));
#550=CARTESIAN_POINT('',(-4.3266362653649,6.13439730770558,-55.2659731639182));
#551=CARTESIAN_POINT('',(-4.31666187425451,6.13573092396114,-56.0023330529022));
#552=CARTESIAN_POINT('',(-4.31446136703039,6.13602504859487,-56.1647266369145));
#553=CARTESIAN_POINT('',(-4.31226006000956,6.13631918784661,-56.3271202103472));
#554=CARTESIAN_POINT('',(-4.30667589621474,6.13706474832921,-56.7386927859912));
#555=CARTESIAN_POINT('',(-4.30109173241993,6.13781030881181,-57.1502653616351));
#556=CARTESIAN_POINT('',(-4.29550756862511,6.13855586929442,-57.5618379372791));
#557=B_SPLINE_CURVE_WITH_KNOTS('',3,(#544,#545,#546,#547,#548,#549,#550,#551,#552,#553,#554,
#555,#556),.UNSPECIFIED.,.F.,.F.,(4,2,2,2,3,4),(0.,1.72202923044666,3.44405845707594,
5.16608767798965,5.65330533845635,6.88811689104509),.UNSPECIFIED.);
#558=EDGE_CURVE('E362',#440,#475,#557,.T.);
#559=ORIENTED_EDGE('',*,*,#558,.F.);
#560=EDGE_LOOP('',(#526,#542,#543,#559));
#561=FACE_BOUND('',#560,.T.);
#562=ADVANCED_FACE('F340',(#561),#425,.T.);
#563=ORIENTED_EDGE('',*,*,#376,.F.);
#564=CARTESIAN_POINT('',(4.18475579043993,6.15325240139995,-65.6675626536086));
#565=CARTESIAN_POINT('',(4.2061557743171,6.15042773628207,-64.1108242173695));
#566=CARTESIAN_POINT('',(4.22748112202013,6.14760430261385,-62.5540847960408));
#567=CARTESIAN_POINT('',(4.26998254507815,6.14195989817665,-59.4406039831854));
#568=CARTESIAN_POINT('',(4.29115862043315,6.13913892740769,-57.8838625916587));
#569=CARTESIAN_POINT('',(4.31226005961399,6.13631918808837,-56.3271202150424));
#570=CARTESIAN_POINT('',(4.31919474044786,6.13539257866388,-55.8155371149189));
#571=CARTESIAN_POINT('',(4.3261215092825,6.13446610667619,-55.3039539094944));
#572=CARTESIAN_POINT('',(4.4324950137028,6.12022439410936,-47.4386841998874));
#573=CARTESIAN_POINT('',(4.53032099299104,6.10693868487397,-40.0849761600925));
#574=CARTESIAN_POINT('',(4.72289271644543,6.08046334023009,-25.3775197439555));
#575=CARTESIAN_POINT('',(4.81763846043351,6.06727370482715,-18.0237713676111));
#576=CARTESIAN_POINT('',(4.9574162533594,6.04761808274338,-7.00347678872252));
#577=CARTESIAN_POINT('',(5.00355511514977,6.04109681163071,-3.33694413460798));
#578=CARTESIAN_POINT('',(5.13120476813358,6.0229740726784,6.88638207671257));
#579=CARTESIAN_POINT('',(5.2119285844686,6.01142020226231,13.44318495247));
#580=CARTESIAN_POINT('',(5.29155383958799,5.99995483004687,19.9999999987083));
#581=CARTESIAN_POINT('',(5.30098107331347,5.99859734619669,20.7762875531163));
#582=CARTESIAN_POINT('',(5.31039288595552,5.99724113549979,21.5525752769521));
#583=CARTESIAN_POINT('',(5.50185157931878,5.96963397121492,37.3698867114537));
#584=CARTESIAN_POINT('',(5.67815807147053,5.94386826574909,52.4109731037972));
#585=CARTESIAN_POINT('',(6.02055984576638,5.89364265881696,82.4932436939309));
#586=CARTESIAN_POINT('',(6.18665512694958,5.86918275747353,97.5344278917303));
#587=CARTESIAN_POINT('',(6.34829490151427,5.84554211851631,112.575645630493));
#588=B_SPLINE_CURVE_WITH_KNOTS('',3,(#564,#565,#566,#567,#568,#569,#570,#571,#572,#573,#574,
#575,#576,#577,#578,#579,#580,#581,#582,#583,#584,#585,#586,#587),.UNSPECIFIED.,.F.,.F.,(4,2,3,
2,2,2,2,3,2,2,4),(0.,4.67058121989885,9.34116243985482,10.8760281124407,32.9387510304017,
55.0014752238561,66.0017702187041,85.6733619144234,88.0023603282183,133.128041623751,
178.253727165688),.UNSPECIFIED.);
#589=EDGE_CURVE('E312',#473,#285,#588,.T.);
#590=ORIENTED_EDGE('',*,*,#589,.F.);
#591=ORIENTED_EDGE('',*,*,#521,.F.);
#592=CARTESIAN_POINT('',(4.86865765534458,6.49999999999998,112.589430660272));
#593=CARTESIAN_POINT('',(4.72854309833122,6.49999999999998,97.5481882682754));
#594=CARTESIAN_POINT('',(4.58570126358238,6.49999999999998,82.506970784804));
#595=CARTESIAN_POINT('',(4.29383527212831,6.49999999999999,52.4245972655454));
#596=CARTESIAN_POINT('',(4.14481111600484,6.49999999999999,37.3834412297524));
#597=CARTESIAN_POINT('',(3.98446224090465,6.49999999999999,21.5660274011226));
#598=CARTESIAN_POINT('',(3.97658337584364,6.49999999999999,20.7897345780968));
#599=CARTESIAN_POINT('',(3.96869525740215,6.49999999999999,20.0134418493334));
#600=CARTESIAN_POINT('',(3.90207066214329,6.49999999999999,13.4565830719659));
#601=CARTESIAN_POINT('',(3.83478660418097,6.49999999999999,6.899731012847));
#602=CARTESIAN_POINT('',(3.72882079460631,6.49999999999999,-3.32368206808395));
#603=CARTESIAN_POINT('',(3.6906048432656,6.49999999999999,-6.99024791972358));
#604=CARTESIAN_POINT('',(3.57509455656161,6.5,-18.0106489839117));
#605=CARTESIAN_POINT('',(3.49714999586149,6.5,-25.3644773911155));
#606=CARTESIAN_POINT('',(3.33949645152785,6.5,-40.0721148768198));
#607=CARTESIAN_POINT('',(3.25978746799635,6.5,-47.4259239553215));
#608=CARTESIAN_POINT('',(3.17357504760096,6.5,-55.291314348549));
#609=CARTESIAN_POINT('',(3.16796316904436,6.5,-55.8029054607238));
#610=CARTESIAN_POINT('',(3.16234694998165,6.5,-56.3144965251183));
#611=CARTESIAN_POINT('',(3.14525697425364,6.5,-57.8712631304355));
#612=CARTESIAN_POINT('',(3.12812658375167,6.5,-59.4280292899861));
#613=CARTESIAN_POINT('',(3.09378497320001,6.5,-62.5415607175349));
#614=CARTESIAN_POINT('',(3.07657375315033,6.5,-64.0983259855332));
#615=CARTESIAN_POINT('',(3.05932211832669,6.5,-65.6550908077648));
#616=B_SPLINE_CURVE_WITH_KNOTS('',3,(#592,#593,#594,#595,#596,#597,#598,#599,#600,#601,#602,
#603,#604,#605,#606,#607,#608,#609,#610,#611,#612,#613,#614,#615),.UNSPECIFIED.,.F.,.F.,(4,2,2,
3,2,2,2,2,3,2,4),(0.,45.1256855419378,90.2513668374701,92.580365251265,112.251956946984,
123.252251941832,145.314976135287,167.377699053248,168.912564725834,173.58314594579,
178.253727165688),.UNSPECIFIED.);
#617=EDGE_CURVE('E436',#375,#503,#616,.T.);
#618=ORIENTED_EDGE('',*,*,#617,.F.);
#619=EDGE_LOOP('',(#563,#590,#591,#618));
#620=FACE_BOUND('',#619,.T.);
#621=ADVANCED_FACE('F249',(#620),#360,.T.);
#622=CARTESIAN_POINT('',(-10.4110305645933,6.5,-56.3271202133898));
#623=DIRECTION('',(0.,1.,0.));
#624=DIRECTION('',(0.,0.,1.));
#625=AXIS2_PLACEMENT_3D('',#622,#623,#624);
#626=PLANE('',#625);
#627=ORIENTED_EDGE('',*,*,#384,.F.);
#628=ORIENTED_EDGE('',*,*,#617,.T.);
#629=ORIENTED_EDGE('',*,*,#504,.T.);
#630=ORIENTED_EDGE('',*,*,#541,.T.);
#631=EDGE_LOOP('',(#627,#628,#629,#630));
#632=FACE_BOUND('',#631,.T.);
#633=ADVANCED_FACE('F398',(#632),#626,.T.);
#634=CARTESIAN_POINT('',(-3.74165738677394,6.5,-56.3271202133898));
#635=CARTESIAN_POINT('',(-3.48711915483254,7.2,20.));
#636=CARTESIAN_POINT('',(-9.38126392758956,3.25361915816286,-56.3271202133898));
#637=CARTESIAN_POINT('',(-10.4110105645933,3.84660633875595,20.));
#638=CARTESIAN_POINT('',(-9.38126392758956,-3.25361915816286,-56.3271202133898));
#639=CARTESIAN_POINT('',(-10.4110105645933,-3.84660633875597,20.));
#640=CARTESIAN_POINT('',(-3.74165738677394,-6.5,-56.3271202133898));
#641=CARTESIAN_POINT('',(-3.48711915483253,-7.2,20.));
#642=(BOUNDED_SURFACE() B_SPLINE_SURFACE(3,1,((#634,#635),(#636,#637),(#638,#639),(#640,#641)),
.UNSPECIFIED.,.F.,.F.,.F.) B_SPLINE_SURFACE_WITH_KNOTS((4,4),(2,2),(0.,1.),(0.,1.),
.UNSPECIFIED.) GEOMETRIC_REPRESENTATION_ITEM() RATIONAL_B_SPLINE_SURFACE(((1.,1.),
(0.665925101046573,0.623926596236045),(0.665925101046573,0.623926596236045),(1.,1.))) REPRESENTATION_ITEM('') SURFACE());
#643=CARTESIAN_POINT('',(0.,0.,-56.3271202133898));
#644=DIRECTION('',(0.,0.,-1.));
#645=DIRECTION('',(-1.,0.,0.));
#646=AXIS2_PLACEMENT_3D('',#643,#644,#645);
#647=CIRCLE('',#646,7.49999985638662);
#648=EDGE_CURVE('E364',#64,#475,#647,.T.);
#649=ORIENTED_EDGE('',*,*,#450,.F.);
#650=ORIENTED_EDGE('',*,*,#558,.T.);
#651=ORIENTED_EDGE('',*,*,#648,.F.);
#652=ORIENTED_EDGE('',*,*,#65,.F.);
#653=ORIENTED_EDGE('',*,*,#257,.F.);
#654=EDGE_LOOP('',(#649,#650,#651,#652,#653));
#655=FACE_BOUND('',#654,.T.);
#656=ADVANCED_FACE('F196',(#655),#642,.T.);
#657=CARTESIAN_POINT('',(0.,0.,-56.3271202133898));
#658=DIRECTION('',(0.,1.,0.));
#659=DIRECTION('',(1.,0.,0.));
#660=AXIS2_PLACEMENT_3D('',#657,#658,#659);
#661=SPHERICAL_SURFACE('',#660,7.49999985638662);
#662=CARTESIAN_POINT('',(0.,0.,-56.3271202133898));
#663=DIRECTION('',(0.,0.,1.));
#664=DIRECTION('',(1.,0.,0.));
#665=AXIS2_PLACEMENT_3D('',#662,#663,#664);
#666=CIRCLE('',#665,7.49999985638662);
#667=EDGE_CURVE('E361',#73,#473,#666,.T.);
#668=ORIENTED_EDGE('',*,*,#667,.F.);
#669=ORIENTED_EDGE('',*,*,#74,.T.);
#670=ORIENTED_EDGE('',*,*,#648,.T.);
#671=ORIENTED_EDGE('',*,*,#476,.F.);
#672=EDGE_LOOP('',(#668,#669,#670,#671));
#673=FACE_BOUND('',#672,.T.);
#674=ADVANCED_FACE('F247',(#673),#661,.T.);
#675=CARTESIAN_POINT('',(3.74165738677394,-6.5,-56.3271202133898));
#676=CARTESIAN_POINT('',(3.48711915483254,-7.2,20.));
#677=CARTESIAN_POINT('',(9.38126392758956,-3.25361915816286,-56.3271202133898));
#678=CARTESIAN_POINT('',(10.4110105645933,-3.84660633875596,20.));
#679=CARTESIAN_POINT('',(9.38126392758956,3.25361915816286,-56.3271202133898));
#680=CARTESIAN_POINT('',(10.4110105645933,3.84660633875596,20.));
#681=CARTESIAN_POINT('',(3.74165738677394,6.5,-56.3271202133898));
#682=CARTESIAN_POINT('',(3.48711915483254,7.2,20.));
#683=(BOUNDED_SURFACE() B_SPLINE_SURFACE(3,1,((#675,#676),(#677,#678),(#679,#680),(#681,#682)),
.UNSPECIFIED.,.F.,.F.,.F.) B_SPLINE_SURFACE_WITH_KNOTS((4,4),(2,2),(0.,1.),(0.,1.),
.UNSPECIFIED.) GEOMETRIC_REPRESENTATION_ITEM() RATIONAL_B_SPLINE_SURFACE(((1.,1.),
(0.665925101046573,0.623926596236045),(0.665925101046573,0.623926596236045),(1.,1.))) REPRESENTATION_ITEM('') SURFACE());
#684=ORIENTED_EDGE('',*,*,#286,.F.);
#685=ORIENTED_EDGE('',*,*,#206,.F.);
#686=ORIENTED_EDGE('',*,*,#83,.F.);
#687=ORIENTED_EDGE('',*,*,#667,.T.);
#688=ORIENTED_EDGE('',*,*,#589,.T.);
#689=EDGE_LOOP('',(#684,#685,#686,#687,#688));
#690=FACE_BOUND('',#689,.T.);
#691=ADVANCED_FACE('F240',(#690),#683,.T.);
#692=CARTESIAN_POINT('',(3.46402017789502,0.0999999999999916,-54.0377883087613));
#693=DIRECTION('',(-0.984807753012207,-0.173648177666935,0.));
#694=DIRECTION('',(0.173648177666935,-0.984807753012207,0.));
#695=AXIS2_PLACEMENT_3D('',#692,#693,#694);
#696=PLANE('',#695);
#697=DIRECTION('',(-0.173648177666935,0.984807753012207,0.));
#698=VECTOR('',#697,1.);
#699=CARTESIAN_POINT('',(3.46402017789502,0.0999999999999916,-62.4463343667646));
#700=LINE('',#699,#698);
#701=CARTESIAN_POINT('',(3.46402017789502,0.0999999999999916,-62.4463343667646));
#702=VERTEX_POINT('',#701);
#703=EDGE_CURVE('E698',#702,#29,#700,.T.);
#704=ORIENTED_EDGE('',*,*,#703,.T.);
#705=ORIENTED_EDGE('',*,*,#32,.T.);
#706=DIRECTION('',(0.,0.,-1.));
#707=VECTOR('',#706,1.);
#708=CARTESIAN_POINT('',(2.93503923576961,3.09999999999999,-54.0377883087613));
#709=LINE('',#708,#707);
#710=CARTESIAN_POINT('',(2.93503923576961,3.09999999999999,-54.0377883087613));
#711=VERTEX_POINT('',#710);
#712=EDGE_CURVE('E144',#711,#31,#709,.T.);
#713=ORIENTED_EDGE('',*,*,#712,.F.);
#714=DIRECTION('',(-0.173648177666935,0.984807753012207,0.));
#715=VECTOR('',#714,1.);
#716=CARTESIAN_POINT('',(3.46402017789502,0.0999999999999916,-54.0377883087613));
#717=LINE('',#716,#715);
#718=CARTESIAN_POINT('',(3.46402017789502,0.0999999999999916,-54.0377883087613));
#719=VERTEX_POINT('',#718);
#720=EDGE_CURVE('E150',#719,#711,#717,.T.);
#721=ORIENTED_EDGE('',*,*,#720,.F.);
#722=DIRECTION('',(0.,0.,-1.));
#723=VECTOR('',#722,1.);
#724=CARTESIAN_POINT('',(3.46402017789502,0.0999999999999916,-54.0377883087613));
#725=LINE('',#724,#723);
#726=EDGE_CURVE('E695',#719,#702,#725,.T.);
#727=ORIENTED_EDGE('',*,*,#726,.T.);
#728=EDGE_LOOP('',(#704,#705,#713,#721,#727));
#729=FACE_BOUND('',#728,.T.);
#730=ADVANCED_FACE('F162',(#729),#696,.F.);
#731=CARTESIAN_POINT('',(2.93503923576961,3.09999999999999,-54.0377883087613));
#732=DIRECTION('',(0.,-1.,0.));
#733=DIRECTION('',(1.,0.,0.));
#734=AXIS2_PLACEMENT_3D('',#731,#732,#733);
#735=PLANE('',#734);
#736=ORIENTED_EDGE('',*,*,#260,.F.);
#737=DIRECTION('',(0.,0.,-1.));
#738=VECTOR('',#737,1.);
#739=CARTESIAN_POINT('',(-2.93503923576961,3.09999999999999,-54.0377883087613));
#740=LINE('',#739,#738);
#741=CARTESIAN_POINT('',(-2.93503923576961,3.09999999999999,-54.0377883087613));
#742=VERTEX_POINT('',#741);
#743=EDGE_CURVE('E146',#742,#47,#740,.T.);
#744=ORIENTED_EDGE('',*,*,#743,.F.);
#745=DIRECTION('',(-1.,0.,0.));
#746=VECTOR('',#745,1.);
#747=CARTESIAN_POINT('',(2.93503923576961,3.09999999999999,-54.0377883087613));
#748=LINE('',#747,#746);
#749=EDGE_CURVE('E139',#711,#742,#748,.T.);
#750=ORIENTED_EDGE('',*,*,#749,.F.);
#751=ORIENTED_EDGE('',*,*,#712,.T.);
#752=EDGE_LOOP('',(#736,#744,#750,#751));
#753=FACE_BOUND('',#752,.T.);
#754=ADVANCED_FACE('F142',(#753),#735,.F.);
#755=CARTESIAN_POINT('',(-2.93503923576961,3.09999999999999,-54.0377883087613));
#756=DIRECTION('',(0.984807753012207,-0.173648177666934,0.));
#757=DIRECTION('',(0.173648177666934,0.984807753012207,0.));
#758=AXIS2_PLACEMENT_3D('',#755,#756,#757);
#759=PLANE('',#758);
#760=DIRECTION('',(-0.173648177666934,-0.984807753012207,0.));
#761=VECTOR('',#760,1.);
#762=CARTESIAN_POINT('',(-2.93503923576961,3.09999999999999,-62.4463343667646));
#763=LINE('',#762,#761);
#764=CARTESIAN_POINT('',(-3.46402017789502,0.0999999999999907,-62.4463343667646));
#765=VERTEX_POINT('',#764);
#766=EDGE_CURVE('E701',#39,#765,#763,.T.);
#767=ORIENTED_EDGE('',*,*,#766,.T.);
#768=DIRECTION('',(0.,0.,-1.));
#769=VECTOR('',#768,1.);
#770=CARTESIAN_POINT('',(-3.46402017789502,0.0999999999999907,-54.0377883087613));
#771=LINE('',#770,#769);
#772=CARTESIAN_POINT('',(-3.46402017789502,0.0999999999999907,-54.0377883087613));
#773=VERTEX_POINT('',#772);
#774=EDGE_CURVE('E167',#773,#765,#771,.T.);
#775=ORIENTED_EDGE('',*,*,#774,.F.);
#776=DIRECTION('',(-0.173648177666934,-0.984807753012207,0.));
#777=VECTOR('',#776,1.);
#778=CARTESIAN_POINT('',(-2.93503923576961,3.09999999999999,-54.0377883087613));
#779=LINE('',#778,#777);
#780=EDGE_CURVE('E149',#742,#773,#779,.T.);
#781=ORIENTED_EDGE('',*,*,#780,.F.);
#782=ORIENTED_EDGE('',*,*,#743,.T.);
#783=ORIENTED_EDGE('',*,*,#48,.T.);
#784=EDGE_LOOP('',(#767,#775,#781,#782,#783));
#785=FACE_BOUND('',#784,.T.);
#786=ADVANCED_FACE('F575',(#785),#759,.F.);
#787=CARTESIAN_POINT('',(-3.46402017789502,0.0999999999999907,-54.0377883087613));
#788=DIRECTION('',(0.,1.,0.));
#789=DIRECTION('',(-1.,0.,0.));
#790=AXIS2_PLACEMENT_3D('',#787,#788,#789);
#791=PLANE('',#790);
#792=DIRECTION('',(1.,0.,0.));
#793=VECTOR('',#792,1.);
#794=CARTESIAN_POINT('',(-3.46402017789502,0.0999999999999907,-62.4463343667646));
#795=LINE('',#794,#793);
#796=EDGE_CURVE('E159',#765,#702,#795,.T.);
#797=ORIENTED_EDGE('',*,*,#796,.T.);
#798=ORIENTED_EDGE('',*,*,#726,.F.);
#799=DIRECTION('',(1.,0.,0.));
#800=VECTOR('',#799,1.);
#801=CARTESIAN_POINT('',(-3.46402017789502,0.0999999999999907,-54.0377883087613));
#802=LINE('',#801,#800);
#803=EDGE_CURVE('E155',#773,#719,#802,.T.);
#804=ORIENTED_EDGE('',*,*,#803,.F.);
#805=ORIENTED_EDGE('',*,*,#774,.T.);
#806=EDGE_LOOP('',(#797,#798,#804,#805));
#807=FACE_BOUND('',#806,.T.);
#808=ADVANCED_FACE('F584',(#807),#791,.F.);
#809=CARTESIAN_POINT('',(0.,0.,-54.0377883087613));
#810=DIRECTION('',(0.,0.,1.));
#811=DIRECTION('',(1.,0.,0.));
#812=AXIS2_PLACEMENT_3D('',#809,#810,#811);
#813=PLANE('',#812);
#814=ORIENTED_EDGE('',*,*,#720,.T.);
#815=ORIENTED_EDGE('',*,*,#749,.T.);
#816=ORIENTED_EDGE('',*,*,#780,.T.);
#817=ORIENTED_EDGE('',*,*,#803,.T.);
#818=EDGE_LOOP('',(#814,#815,#816,#817));
#819=FACE_BOUND('',#818,.T.);
#820=ADVANCED_FACE('F153',(#819),#813,.T.);
#821=CARTESIAN_POINT('',(0.,0.,-62.4463343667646));
#822=DIRECTION('',(0.,0.,1.));
#823=DIRECTION('',(1.,0.,0.));
#824=AXIS2_PLACEMENT_3D('',#821,#822,#823);
#825=PLANE('',#824);
#826=ORIENTED_EDGE('',*,*,#703,.F.);
#827=ORIENTED_EDGE('',*,*,#796,.F.);
#828=ORIENTED_EDGE('',*,*,#766,.F.);
#829=ORIENTED_EDGE('',*,*,#40,.F.);
#830=EDGE_LOOP('',(#826,#827,#828,#829));
#831=FACE_BOUND('',#830,.T.);
#832=ADVANCED_FACE('F604',(#831),#825,.F.);
#833=CLOSED_SHELL('',(#89,#131,#147,#163,#271,#455,#525,#562,#621,#633,#656,#674,#691,#730,#754,
#786,#808,#820,#832));
#834=MANIFOLD_SOLID_BREP('B2',#833);
#835=ADVANCED_BREP_SHAPE_REPRESENTATION('',(#18,#834),#14);
#836=SHAPE_DEFINITION_REPRESENTATION(#9,#835);
ENDSEC;
END-ISO-10303-21;
